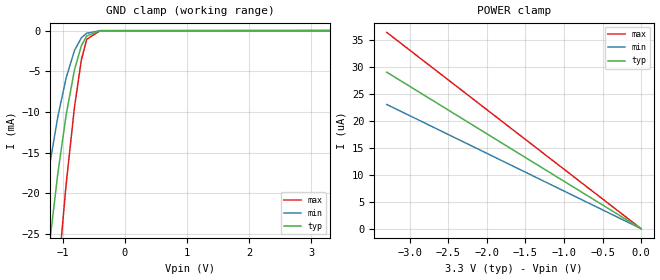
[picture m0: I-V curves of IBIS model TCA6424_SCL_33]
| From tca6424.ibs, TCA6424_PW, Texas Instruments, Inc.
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[Model]   TCA6424_SCL_33
Model_type  Input
Vinl=0.9
Vinh=2.52
| variable   typ   min   max
C_comp   2.17pF   1.72pF   2.37pF
[Temperature Range]   40   100   -40
| Ambient temperature   25   85   -40
[Voltage range]   3.3   3   3.6
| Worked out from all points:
|   GND clamp passes 1 mA (typ) near -0.65 V on its own axis
[GND Clamp]
| TCA6424_SCL_33
|   Voltage   I(typ)   I(min)   I(max)
-3.3V     -229.8mA   -173.1mA   -314.8mA
-1.49V    -47.01mA   -31.58mA   -73.96mA
-1.455V   -44.17mA   -29.5mA    -69.91mA
-1.285V   -31.2mA    -20.13mA   -51.01mA
-1.255V   -29.06mA   -18.61mA   -47.84mA
-1.08V    -17.66mA   -10.65mA   -30.52mA
-945mV    -10.38mA   -5.815mA   -18.91mA
-810mV    -4.804mA   -2.432mA   -9.37mA
-700mV    -1.866mA   -886.6uA   -3.615mA
-615mV    -659.7uA   -324.3uA   -1.075mA
-400mV    -14.1uA    -11.42uA   -12.78uA
3.3V      289.3pA    2.092uA    -3.305uA
[POWER Clamp]
| TCA6424_SCL_33
|   Voltage   I(typ)   I(min)   I(max)
-3.3V     28.99uA    23.01uA    36.36uA
-2.98V    26.18uA    20.78uA    32.83uA
-1.81V    15.9uA     12.62uA    19.94uA
-48.03fV  289.3pA    907.4pA    66.29pA
